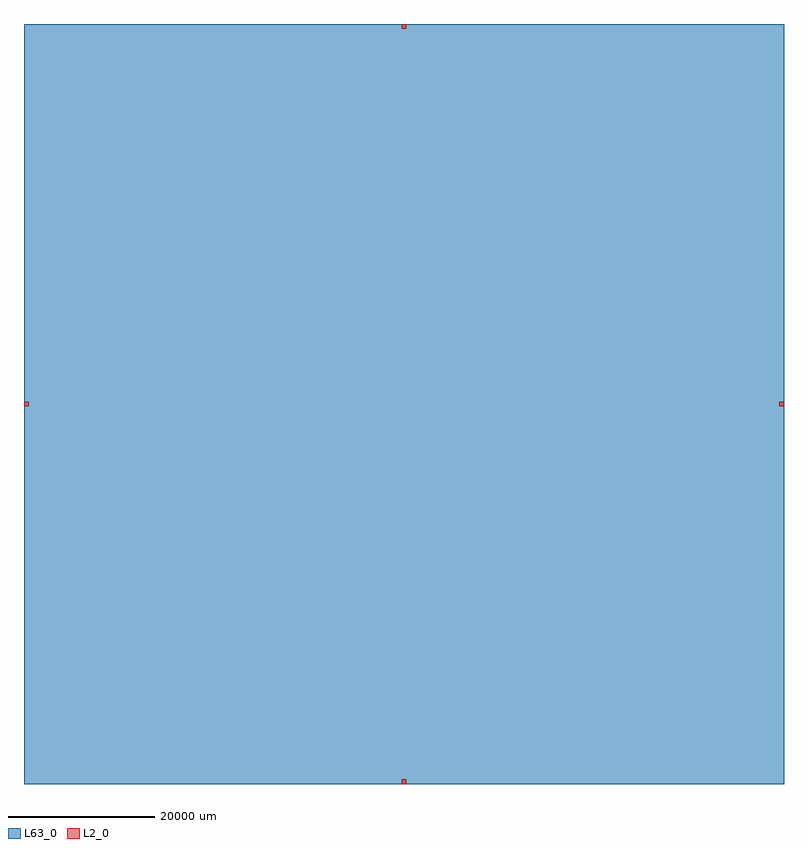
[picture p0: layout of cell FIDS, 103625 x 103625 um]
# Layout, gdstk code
import gdstk
lib = gdstk.Library(unit=1e-6, precision=1e-09)
def R(c, l, rs):  # rectangles x0, y0, x1, y1
    for r in rs: c.add(gdstk.rectangle(r[:2], r[2:], *l))
L2_0 = (2, 0)
L63_0 = (63, 0)

fid = lib.new_cell('FID')
R(fid, L2_0, [(-312.5,-312.5,-12.5,-12.5), (12.5,-312.5,312.5,-12.5), (-312.5,12.5,-12.5,312.5), (12.5,12.5,312.5,312.5)])
R(fid, L63_0, [(-312.5,-312.5,312.5,312.5)])

fids = lib.new_cell('FIDS')
R(fids, L63_0, [(-51812.5,-51812.5,51812.5,51812.5)])
fids.add(gdstk.Reference(fid, (-51500,0)))
fids.add(gdstk.Reference(fid, (51500,0)))
fids.add(gdstk.Reference(fid, (0,51500)))
fids.add(gdstk.Reference(fid, (0,-51500)))

lib.write_gds('FIDS.gds')
